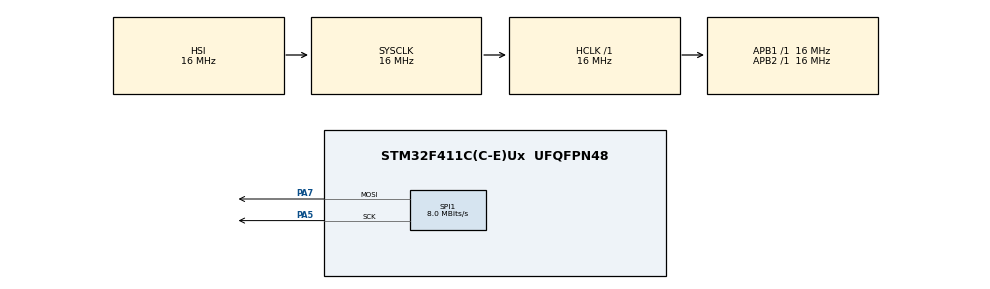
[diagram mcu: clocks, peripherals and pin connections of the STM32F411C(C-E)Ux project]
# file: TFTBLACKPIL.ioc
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Mcu.Family=STM32F4
Mcu.Name=STM32F411C(C-E)Ux
Mcu.Package=UFQFPN48
NVIC.PriorityGroup=NVIC_PRIORITYGROUP_4
PA5.Mode=TX_Only_Simplex_Unidirect_Master
PA5.Signal=SPI1_SCK
PA7.Mode=TX_Only_Simplex_Unidirect_Master
PA7.Signal=SPI1_MOSI
ProjectManager.HeapSize=0x200
ProjectManager.StackSize=0x400
ProjectManager.TargetToolchain=STM32CubeIDE
RCC.AHBFreq_Value=16000000
RCC.APB1Freq_Value=16000000
RCC.APB2Freq_Value=16000000
RCC.CortexFreq_Value=16000000
RCC.HSE_VALUE=25000000
RCC.HSI_VALUE=16000000
RCC.LSE_VALUE=32768
RCC.SYSCLKFreq_VALUE=16000000
RCC.VCOOutputFreq_Value=192000000
SPI1.CalculateBaudRate=8.0 MBits/s
SPI1.Direction=SPI_DIRECTION_2LINES
SPI1.Mode=SPI_MODE_MASTER
SPI1.VirtualType=VM_MASTER
board=custom

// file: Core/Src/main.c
/*
 * A3 CS
 * A4 DC
 * A5 SCK
 * A6 RES
 * A7 MOSI
 * */
#include "main.h"
#include "stm32f4xx_hal.h"

/* USER CODE BEGIN Includes */
/* vim: set ai et ts=4 sw=4: */
#include <string.h>
#include "st7735.h"
#include "fonts.h"
//#include "testimg.h"

SPI_HandleTypeDef hspi1;

void SystemClock_Config(void);
static void MX_GPIO_Init(void);
static void MX_SPI1_Init(void);

void init() {
    ST7735_Init();

    //const char ready[] = "Ready!\r\n";
    //HAL_UART_Transmit(&huart2, (uint8_t*)ready, sizeof(ready)-1, HAL_MAX_DELAY);
}

void loop() {
    // Check border

    ST7735_FillScreen(ST7735_BLACK);

    for(int x = 0; x < ST7735_WIDTH; x++) {
        ST7735_DrawPixel(x, 0, ST7735_RED);
        ST7735_DrawPixel(x, ST7735_HEIGHT-1, ST7735_RED);
    }

    for(int y = 0; y < ST7735_HEIGHT; y++) {
        ST7735_DrawPixel(0, y, ST7735_RED);
        ST7735_DrawPixel(ST7735_WIDTH-1, y, ST7735_RED);
    }

    //HAL_Delay(3000);

    // Check fonts
    ST7735_FillScreen(ST7735_BLACK);
    ST7735_WriteString(0, 0, "Font_7x10, red on black, lorem ipsum dolor sit amet", Font_7x10, ST7735_RED, ST7735_BLACK);
    ST7735_WriteString(0, 3*10, "Font_11x18, green, lorem ipsum", Font_11x18, ST7735_GREEN, ST7735_BLACK);
    ST7735_WriteString(0, 3*10+3*18, "Font_16x26", Font_16x26, ST7735_BLUE, ST7735_BLACK);
    HAL_Delay(2000);

    // Check colors
    ST7735_FillScreen(ST7735_BLACK);
    ST7735_WriteString(0, 0, "BLACK", Font_11x18, ST7735_WHITE, ST7735_BLACK);
    HAL_Delay(500);

    ST7735_FillScreen(ST7735_BLUE);
    ST7735_WriteString(0, 0, "BLUE", Font_11x18, ST7735_BLACK, ST7735_BLUE);
    HAL_Delay(500);

    ST7735_FillScreen(ST7735_RED);
    ST7735_WriteString(0, 0, "RED", Font_11x18, ST7735_BLACK, ST7735_RED);
    HAL_Delay(500);

    ST7735_FillScreen(ST7735_GREEN);
    ST7735_WriteString(0, 0, "GREEN", Font_11x18, ST7735_BLACK, ST7735_GREEN);
    HAL_Delay(500);

    ST7735_FillScreen(ST7735_CYAN);
    ST7735_WriteString(0, 0, "CYAN", Font_11x18, ST7735_BLACK, ST7735_CYAN);
    HAL_Delay(500);

    ST7735_FillScreen(ST7735_MAGENTA);
    ST7735_WriteString(0, 0, "MAGENTA", Font_11x18, ST7735_BLACK, ST7735_MAGENTA);
    HAL_Delay(500);

    ST7735_FillScreen(ST7735_YELLOW);
    ST7735_WriteString(0, 0, "YELLOW", Font_11x18, ST7735_BLACK, ST7735_YELLOW);
    HAL_Delay(500);

    ST7735_FillScreen(ST7735_WHITE);
    ST7735_WriteString(0, 0, "WHITE", Font_11x18, ST7735_BLACK, ST7735_WHITE);
    HAL_Delay(500);

#ifdef ST7735_IS_128X128
    // Display test image 128x128
    ST7735_DrawImage(0, 0, ST7735_WIDTH, ST7735_HEIGHT, (uint16_t*)test_img_128x128);

/*
    // Display test image 128x128 pixel by pixel
    for(int x = 0; x < ST7735_WIDTH; x++) {
        for(int y = 0; y < ST7735_HEIGHT; y++) {
            uint16_t color565 = test_img_128x128[y][x];
            // fix endiness
            color565 = ((color565 & 0xFF00) >> 8) | ((color565 & 0xFF) << 8);
            ST7735_DrawPixel(x, y, color565);
        }
    }
*/
    HAL_Delay(15000);
#endif // ST7735_IS_128X128

}

int main(void)
{
  HAL_Init();
  SystemClock_Config();
  MX_GPIO_Init();
  MX_SPI1_Init();
  init();
  ST7735_FillScreen(ST7735_BLACK);
  ST7735_WriteString(0, 0, "INGRESA EL TAMANO DEL SISTEMA NxN:", Font_7x10, ST7735_CYAN, ST7735_BLACK);

  while (1)
  {
    /* USER CODE END WHILE */

  }
}

void SystemClock_Config(void)
{
  RCC_OscInitTypeDef RCC_OscInitStruct = {0};
  RCC_ClkInitTypeDef RCC_ClkInitStruct = {0};

  /** Configure the main internal regulator output voltage
  */
  __HAL_RCC_PWR_CLK_ENABLE();
  __HAL_PWR_VOLTAGESCALING_CONFIG(PWR_REGULATOR_VOLTAGE_SCALE3);

  /** Initializes the RCC Oscillators according to the specified parameters
  * in the RCC_OscInitTypeDef structure.
  */
  RCC_OscInitStruct.OscillatorType = RCC_OSCILLATORTYPE_HSI;
  RCC_OscInitStruct.HSIState = RCC_HSI_ON;
  RCC_OscInitStruct.HSICalibrationValue = RCC_HSICALIBRATION_DEFAULT;
  RCC_OscInitStruct.PLL.PLLState = RCC_PLL_NONE;
  if (HAL_RCC_OscConfig(&RCC_OscInitStruct) != HAL_OK)
  {
    Error_Handler();
  }

  /** Initializes the CPU, AHB and APB buses clocks
  */
  RCC_ClkInitStruct.ClockType = RCC_CLOCKTYPE_HCLK|RCC_CLOCKTYPE_SYSCLK
                              |RCC_CLOCKTYPE_PCLK1|RCC_CLOCKTYPE_PCLK2;
  RCC_ClkInitStruct.SYSCLKSource = RCC_SYSCLKSOURCE_HSI;
  RCC_ClkInitStruct.AHBCLKDivider = RCC_SYSCLK_DIV1;
  RCC_ClkInitStruct.APB1CLKDivider = RCC_HCLK_DIV1;
  RCC_ClkInitStruct.APB2CLKDivider = RCC_HCLK_DIV1;

  if (HAL_RCC_ClockConfig(&RCC_ClkInitStruct, FLASH_LATENCY_0) != HAL_OK)
  {
    Error_Handler();
  }
}

static void MX_SPI1_Init(void)
{

  /* SPI1 parameter configuration*/
  hspi1.Instance = SPI1;
  hspi1.Init.Mode = SPI_MODE_MASTER;
  hspi1.Init.Direction = SPI_DIRECTION_2LINES;
  hspi1.Init.DataSize = SPI_DATASIZE_8BIT;
  hspi1.Init.CLKPolarity = SPI_POLARITY_LOW;
  hspi1.Init.CLKPhase = SPI_PHASE_1EDGE;
  hspi1.Init.NSS = SPI_NSS_SOFT;
  hspi1.Init.BaudRatePrescaler = SPI_BAUDRATEPRESCALER_2;
  hspi1.Init.FirstBit = SPI_FIRSTBIT_MSB;
  hspi1.Init.TIMode = SPI_TIMODE_DISABLE;
  hspi1.Init.CRCCalculation = SPI_CRCCALCULATION_DISABLE;
  hspi1.Init.CRCPolynomial = 10;
  if (HAL_SPI_Init(&hspi1) != HAL_OK)
  {
    Error_Handler();
  }

}

static void MX_GPIO_Init(void)
{
	GPIO_InitTypeDef GPIO_InitStruct;

  /* GPIO Ports Clock Enable */
  __HAL_RCC_GPIOA_CLK_ENABLE();
  __HAL_RCC_GPIOB_CLK_ENABLE();

  /*Configure GPIO pin Output Level */
    HAL_GPIO_WritePin(GPIOA, GPIO_PIN_3, GPIO_PIN_RESET);

    /*Configure GPIO pin Output Level */
    HAL_GPIO_WritePin(GPIOA, GPIO_PIN_4, GPIO_PIN_RESET);

    /*Configure GPIO pin Output Level */
    HAL_GPIO_WritePin(GPIOA, GPIO_PIN_6, GPIO_PIN_RESET);

    /*Configure GPIO pin : PA6 */
    GPIO_InitStruct.Pin = GPIO_PIN_6;
    GPIO_InitStruct.Mode = GPIO_MODE_OUTPUT_PP;
    GPIO_InitStruct.Pull = GPIO_NOPULL;
    GPIO_InitStruct.Speed = GPIO_SPEED_FREQ_LOW;
    HAL_GPIO_Init(GPIOA, &GPIO_InitStruct);

    /*Configure GPIO pin : PA4 */
    GPIO_InitStruct.Pin = GPIO_PIN_4;
    GPIO_InitStruct.Mode = GPIO_MODE_OUTPUT_PP;
    GPIO_InitStruct.Pull = GPIO_NOPULL;
    GPIO_InitStruct.Speed = GPIO_SPEED_FREQ_LOW;
    HAL_GPIO_Init(GPIOA, &GPIO_InitStruct);

    /*Configure GPIO pin : PA3 */
    GPIO_InitStruct.Pin = GPIO_PIN_3;
    GPIO_InitStruct.Mode = GPIO_MODE_OUTPUT_PP;
    GPIO_InitStruct.Pull = GPIO_NOPULL;
    GPIO_InitStruct.Speed = GPIO_SPEED_FREQ_LOW;
    HAL_GPIO_Init(GPIOA, &GPIO_InitStruct);
}

void Error_Handler(void)
{
  __disable_irq();
  while (1)
  {
  }
}
